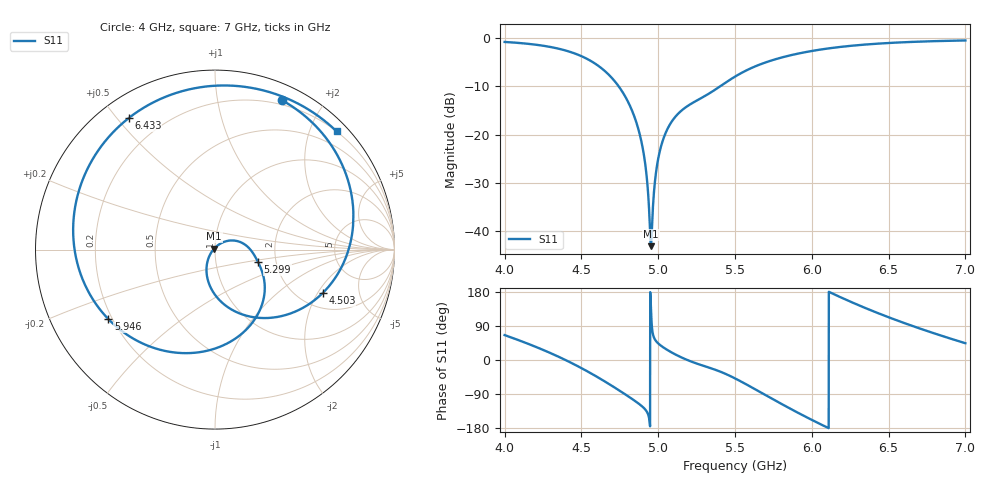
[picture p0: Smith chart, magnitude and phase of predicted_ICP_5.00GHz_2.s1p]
! ICP-predicted S11, target max centred GHz at -10 dB. Complex ensemble mean (passive and causal);
! its |S11| can differ slightly from the dB-domain mean reported in designs.csv.
!  Air_gap = 3.52mm
!  W_Patch = 17.85mm
!  L_Patch = 19.04mm
!  Sx = 2.68mm
!  Sy = 4.46mm
!  W_Patch1 = 15.38mm
!  WS = 0.68mm
!  Curve_Amp1 = 0.74mm
!  Extra = 2.28mm
# GHz S MA R 50
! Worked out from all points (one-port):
!   3001 points, 4 GHz to 7 GHz, reference 50 ohm
!   lowest |S11| = -43.1 dB at 4.953 GHz (marker M1), VSWR 1.01, Z = 49.5 + j0.504 ohm
!   |S11| at or under -10 dB: 4.743 GHz to 5.403 GHz (660.1 MHz wide, 13 % of centre)
!   S11 on the Smith chart (normalised r, x): 4 GHz: 0.16, +1.54; 4.503 GHz: 2.65, -2.21; 5.299 GHz: 1.61, -0.23; 5.946 GHz: 0.18, -0.29; 6.433 GHz: 0.09, +0.54; 7 GHz: 0.20, +2.45
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4  0.9119 65.7
4.212  0.8503 33.2
4.375  0.76 4.1
4.503  0.6465 -22.0
4.627  0.4925 -50.4
4.75  0.3047 -81.3
4.829  0.1784 -102.5
4.885  0.09302 -119.0
4.917  0.04761 -131.2
4.943  0.01408 -159.0
4.953  0.006996 133.3
4.962  0.01372 76.4
4.986  0.04091 49.8
5.013  0.07007 39.3
5.059  0.1134 26.6
5.125  0.1618 11.9
5.299  0.2486 -15.9
5.5  0.3988 -48.5
5.597  0.4816 -69.5
5.706  0.5645 -94.2
5.875  0.6712 -131.7
5.946  0.709 -146.9
6.098  0.7774 -177.5
6.25  0.8302 154.2
6.433  0.8763 123.3
6.625  0.9091 94.2
6.798  0.9291 70.2
7  0.9448 44.2
